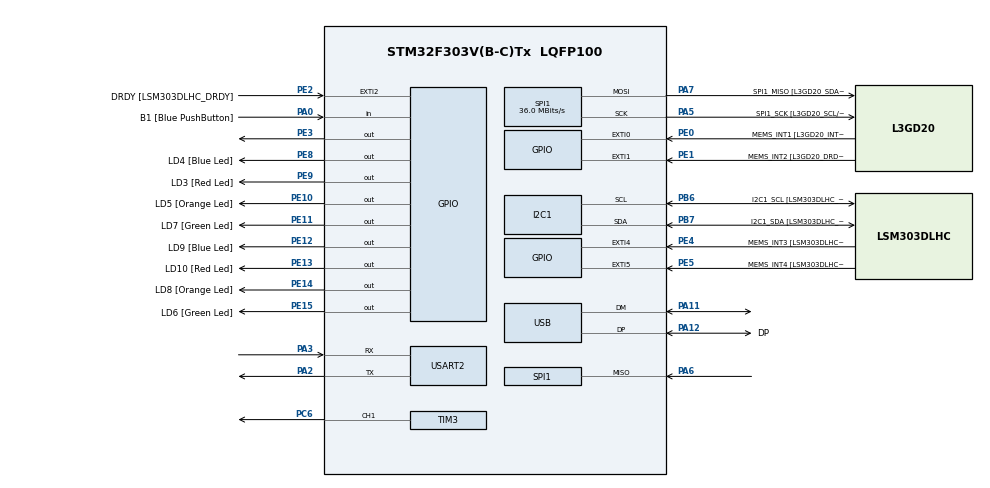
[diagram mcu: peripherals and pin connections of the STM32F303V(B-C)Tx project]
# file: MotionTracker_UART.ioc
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I2C1.Timing=0x00201D2B
I2C1.Timing-I2C=0x2000090E
Mcu.Family=STM32F3
Mcu.Name=STM32F303V(B-C)Tx
Mcu.Package=LQFP100
NVIC.PriorityGroup=NVIC_PRIORITYGROUP_0
NVIC.USART2_IRQn=true\:0\:0\:false\:false\:true\:true\:true\:true
NVIC.USB_LP_CAN_RX0_IRQn=true\:0\:0\:false\:false\:true\:true\:true\:true
PA0.GPIO_Label=B1 [Blue PushButton]
PA0.Signal=GPIO_Input
PA11.Mode=Device
PA11.Signal=USB_DM
PA12.GPIO_Label=DP
PA12.Mode=Device
PA12.Signal=USB_DP
PA13.GPIO_Label=SWDIO
PA13.Mode=Serial_Wire
PA13.Signal=SYS_JTMS-SWDIO
PA14.GPIO_Label=SWCLK
PA14.Mode=Serial_Wire
PA14.Signal=SYS_JTCK-SWCLK
PA2.Mode=Asynchronous
PA2.Signal=USART2_TX
PA3.Mode=Asynchronous
PA3.Signal=USART2_RX
PA5.GPIO_Label=SPI1_SCK [L3GD20_SCL/SPC]
PA5.Mode=Full_Duplex_Master
PA5.Signal=SPI1_SCK
PA6.Mode=Full_Duplex_Master
PA6.Signal=SPI1_MISO
PA7.GPIO_Label=SPI1_MISO [L3GD20_SDA/SDI/SDO]
PA7.Mode=Full_Duplex_Master
PA7.Signal=SPI1_MOSI
PB3.GPIO_Label=SWO
PB3.Signal=SYS_JTDO-TRACESWO
PB6.GPIO_Label=I2C1_SCL [LSM303DLHC_SCL]
PB6.GPIO_Pu=GPIO_PULLUP
PB6.Mode=I2C
PB6.Signal=I2C1_SCL
PB7.GPIO_Label=I2C1_SDA [LSM303DLHC_SDA]
PB7.GPIO_Pu=GPIO_PULLUP
PB7.Mode=I2C
PB7.Signal=I2C1_SDA
PC14-OSC32_IN.GPIO_Label=OSC32_IN
PC14-OSC32_IN.Signal=RCC_OSC32_IN
PC15-OSC32_OUT.GPIO_Label=OSC32_OUT
PC15-OSC32_OUT.Signal=RCC_OSC32_OUT
PC6.Signal=S_TIM3_CH1
PE0.GPIO_Label=MEMS_INT1 [L3GD20_INT1]
PE0.GPIO_ModeDefaultEXTI=GPIO_MODE_EVT_RISING
PE0.Signal=GPXTI0
PE1.GPIO_Label=MEMS_INT2 [L3GD20_DRDY/INT2]
PE1.GPIO_ModeDefaultEXTI=GPIO_MODE_EVT_RISING
PE1.Signal=GPXTI1
PE10.GPIO_Label=LD5 [Orange Led]
PE10.Signal=GPIO_Output
PE11.GPIO_Label=LD7 [Green Led]
PE11.Signal=GPIO_Output
PE12.GPIO_Label=LD9 [Blue Led]
PE12.Signal=GPIO_Output
PE13.GPIO_Label=LD10 [Red Led]
PE13.Signal=GPIO_Output
PE14.GPIO_Label=LD8 [Orange Led]
PE14.Signal=GPIO_Output
PE15.GPIO_Label=LD6 [Green Led]
PE15.Signal=GPIO_Output
PE2.GPIO_Label=DRDY [LSM303DLHC_DRDY]
PE2.GPIO_ModeDefaultEXTI=GPIO_MODE_EVT_RISING
PE2.Signal=GPXTI2
PE3.Signal=GPIO_Output
PE4.GPIO_Label=MEMS_INT3 [LSM303DLHC_INT1]
PE4.GPIO_ModeDefaultEXTI=GPIO_MODE_EVT_RISING
PE4.Signal=GPXTI4
PE5.GPIO_Label=MEMS_INT4 [LSM303DLHC_INT2]
PE5.GPIO_ModeDefaultEXTI=GPIO_MODE_EVT_RISING
PE5.Signal=GPXTI5
PE8.GPIO_Label=LD4 [Blue Led]
PE8.Signal=GPIO_Output
PE9.GPIO_Label=LD3 [Red Led]
PE9.Signal=GPIO_Output
PF0-OSC_IN.GPIO_Label=OSC_IN
PF0-OSC_IN.Mode=HSE-External-Clock-Source
PF0-OSC_IN.Signal=RCC_OSC_IN
PF1-OSC_OUT.GPIO_Label=OSC_OUT
PF1-OSC_OUT.Signal=RCC_OSC_OUT
ProjectManager.HeapSize=0x200
ProjectManager.StackSize=0x400
ProjectManager.TargetToolchain=STM32CubeIDE
RCC.AHBFreq_Value=72000000
RCC.APB1Freq_Value=72000000
RCC.APB1TimFreq_Value=72000000
RCC.APB2Freq_Value=72000000
RCC.APB2TimFreq_Value=72000000
RCC.CortexFreq_Value=72000000
RCC.HCLKFreq_Value=72000000
RCC.HSE_VALUE=8000000
RCC.HSI_VALUE=8000000
RCC.LSE_VALUE=32768
RCC.PLLMUL=RCC_PLL_MUL9
RCC.SYSCLKFreq_VALUE=72000000
RCC.SYSCLKSourceVirtual=RCC_SYSCLKSOURCE_PLLCLK
RCC.USBFreq_Value=72000000
SH.S_TIM3_CH1.0=TIM3_CH1,PWM Generation1 CH1
SPI1.BaudRatePrescaler=SPI_BAUDRATEPRESCALER_2
SPI1.CalculateBaudRate=36.0 MBits/s
SPI1.Direction=SPI_DIRECTION_2LINES
SPI1.Mode=SPI_MODE_MASTER
SPI1.VirtualType=VM_MASTER
TIM3.Channel-PWM\ Generation1\ CH1=TIM_CHANNEL_1
TIM3.Period=999
TIM3.Prescaler=71
USART2.VirtualMode-Asynchronous=VM_ASYNC
VP_TIM3_VS_ClockSourceINT.Mode=Internal
board=STM32F3DISCOVERY

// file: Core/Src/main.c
/* USER CODE BEGIN Header */
/**
  ******************************************************************************
  * @file           : main.c
  * @brief          : Gyroscope-Based Motor Control
  ******************************************************************************
  */
/* USER CODE END Header */

#include "main.h"
#include "tim.h"
#include "usart.h"
#include "gpio.h"
#include "spi.h"
#include "i2c.h"
#include <string.h>
#include <stdio.h>
#include <math.h>
#include "motor.h"

// --- Definitions ---
typedef struct {
    float x;
    float y;
    float z;
    float magnitude;
} L3GD20_Data_t;

#define UART_BUFFER_SIZE 256
#define RX_BUFFER_SIZE 64

// --- Global Variables ---
L3GD20_Data_t gyro_data;
uint8_t current_motor_speed = 0;
uint32_t loop_counter = 0;
char uart_msg[UART_BUFFER_SIZE];

volatile uint8_t motorSpeed = 0;
char debugMsg[UART_BUFFER_SIZE];
uint8_t rxBuffer[RX_BUFFER_SIZE];  // RX_BUFFER_SIZE main.h içinde 64 olarak tanımlanmalı

// --- Function Prototypes ---
void SystemClock_Config(void);
void SendDebugMessage(const char* message);
void L3GD20_Init(void);
void L3GD20_ReadData(L3GD20_Data_t* data);
uint8_t L3GD20_ReadRegister(uint8_t reg);
void L3GD20_WriteRegister(uint8_t reg, uint8_t value);
uint8_t L3GD20_CalculateMotorSpeed(L3GD20_Data_t* gyro_data);
void L3GD20_DisplayOnTerminal(L3GD20_Data_t* gyro_data, uint8_t motor_speed);

// LED Functions - STM32F3 Discovery LEDs
void LED_Init_All(void);
void LED_Set_All(uint8_t state);
void LED_Rainbow_Effect(void);
void LED_Speed_Display(uint8_t speed);
void LED_Gyro_Effect(L3GD20_Data_t* gyro_data);

// Motor functions from motor.c
void HW153_SetMotor(uint8_t speed, uint8_t direction);
#define MOTOR_DIRECTION_FORWARD  1
#define MOTOR_DIRECTION_BACKWARD 0

int main(void)
{
   HAL_Init();
  SystemClock_Config();
  MX_GPIO_Init();
  MX_TIM3_Init();
  MX_USART2_UART_Init();
  MX_SPI1_Init();
  MX_I2C1_Init();

  HAL_Delay(1000);
  HAL_UART_Transmit(&huart2, (uint8_t*)"STM32 Başlatıldı\r\n", 21, HAL_MAX_DELAY);

  Motor_Init();
  L3GD20_Init();
  LED_Init_All();  // Tüm LED'leri başlat

  // Startup LED Show! 🌈
  for(int i = 0; i < 3; i++) {
    LED_Rainbow_Effect();
    HAL_Delay(200);
  }

  HAL_UART_Transmit(&huart2, (uint8_t*)"🌈 LED Show Tamamlandı! 🎉\r\n", 35, HAL_MAX_DELAY);

  while (1)
  {
    L3GD20_ReadData(&gyro_data);
    current_motor_speed = L3GD20_CalculateMotorSpeed(&gyro_data);
    HW153_SetMotor(current_motor_speed, MOTOR_DIRECTION_FORWARD);

    // LED Effects! ✨
    LED_Speed_Display(current_motor_speed);  // Motor hızına göre LED'ler
    LED_Gyro_Effect(&gyro_data);             // Gyroscope efekti

    if (loop_counter % 3 == 0)
    {
        L3GD20_DisplayOnTerminal(&gyro_data, current_motor_speed);
    }

    sprintf(uart_msg, "Gyro[X:%.1f Y:%.1f Z:%.1f] |%.1f| -> Motor:%d%%\r\n",
            gyro_data.x, gyro_data.y, gyro_data.z, gyro_data.magnitude, current_motor_speed);
    SendDebugMessage(uart_msg);

    loop_counter++;
    HAL_Delay(500);
  }
}

void SendDebugMessage(const char* message)
{
    HAL_UART_Transmit(&huart2, (uint8_t*)message, strlen(message), HAL_MAX_DELAY);
}

void L3GD20_Init(void)
{
    HAL_GPIO_WritePin(GPIOE, GPIO_PIN_3, GPIO_PIN_SET);
    HAL_Delay(10);
    L3GD20_WriteRegister(0x20, 0xFF);
    HAL_Delay(10);
    L3GD20_WriteRegister(0x23, 0x00);
    HAL_Delay(10);
}

void L3GD20_ReadData(L3GD20_Data_t* data)
{
    uint8_t buffer[6];
    int16_t raw_x, raw_y, raw_z;

    buffer[0] = L3GD20_ReadRegister(0x28);
    buffer[1] = L3GD20_ReadRegister(0x29);
    buffer[2] = L3GD20_ReadRegister(0x2A);
    buffer[3] = L3GD20_ReadRegister(0x2B);
    buffer[4] = L3GD20_ReadRegister(0x2C);
    buffer[5] = L3GD20_ReadRegister(0x2D);

    raw_x = (int16_t)((buffer[1] << 8) | buffer[0]);
    raw_y = (int16_t)((buffer[3] << 8) | buffer[2]);
    raw_z = (int16_t)((buffer[5] << 8) | buffer[4]);

    data->x = (float)raw_x * 0.00875f;
    data->y = (float)raw_y * 0.00875f;
    data->z = (float)raw_z * 0.00875f;

    data->magnitude = sqrtf(data->x * data->x + data->y * data->y + data->z * data->z);
}

uint8_t L3GD20_ReadRegister(uint8_t reg)
{
    uint8_t tx = reg | 0x80;
    uint8_t rx = 0;

    HAL_GPIO_WritePin(GPIOE, GPIO_PIN_3, GPIO_PIN_RESET);
    HAL_SPI_Transmit(&hspi1, &tx, 1, HAL_MAX_DELAY);
    HAL_SPI_Receive(&hspi1, &rx, 1, HAL_MAX_DELAY);
    HAL_GPIO_WritePin(GPIOE, GPIO_PIN_3, GPIO_PIN_SET);

    return rx;
}

void L3GD20_WriteRegister(uint8_t reg, uint8_t value)
{
    uint8_t tx[2] = {reg, value};
    HAL_GPIO_WritePin(GPIOE, GPIO_PIN_3, GPIO_PIN_RESET);
    HAL_SPI_Transmit(&hspi1, tx, 2, HAL_MAX_DELAY);
    HAL_GPIO_WritePin(GPIOE, GPIO_PIN_3, GPIO_PIN_SET);
}

uint8_t L3GD20_CalculateMotorSpeed(L3GD20_Data_t* gyro_data)
{
    float magnitude = gyro_data->magnitude;
    if (magnitude < 0.5f) return 0;
    if (magnitude > 10.0f) return 100;
    return (uint8_t)(((magnitude - 0.5f) / 9.5f) * 100);
}

void L3GD20_DisplayOnTerminal(L3GD20_Data_t* gyro_data, uint8_t motor_speed)
{
    char msg[128];
    sprintf(msg, "Gyro X: %.2f Y: %.2f Z: %.2f\r\n", gyro_data->x, gyro_data->y, gyro_data->z);
    SendDebugMessage(msg);
    sprintf(msg, "Magnitude: %.2f dps | Motor: %d%%\r\n\r\n", gyro_data->magnitude, motor_speed);
    SendDebugMessage(msg);
}

void Error_Handler(void)
{
  __disable_irq();
  while (1)
  {
    HAL_GPIO_TogglePin(GPIOE, GPIO_PIN_15);
    HAL_Delay(200);
  }
}

void SystemClock_Config(void)
{
    RCC_OscInitTypeDef RCC_OscInitStruct = {0};
    RCC_ClkInitTypeDef RCC_ClkInitStruct = {0};

    RCC_OscInitStruct.OscillatorType = RCC_OSCILLATORTYPE_HSE;
    RCC_OscInitStruct.HSEState = RCC_HSE_BYPASS;
    RCC_OscInitStruct.PLL.PLLState = RCC_PLL_ON;
    RCC_OscInitStruct.PLL.PLLSource = RCC_PLLSOURCE_HSE;
    RCC_OscInitStruct.PLL.PLLMUL = RCC_PLL_MUL9;
    HAL_RCC_OscConfig(&RCC_OscInitStruct);

    RCC_ClkInitStruct.ClockType = RCC_CLOCKTYPE_SYSCLK|RCC_CLOCKTYPE_HCLK
                                  |RCC_CLOCKTYPE_PCLK1|RCC_CLOCKTYPE_PCLK2;
    RCC_ClkInitStruct.SYSCLKSource = RCC_SYSCLKSOURCE_PLLCLK;
    RCC_ClkInitStruct.AHBCLKDivider = RCC_SYSCLK_DIV1;
    RCC_ClkInitStruct.APB1CLKDivider = RCC_HCLK_DIV2;
    RCC_ClkInitStruct.APB2CLKDivider = RCC_HCLK_DIV1;
    HAL_RCC_ClockConfig(&RCC_ClkInitStruct, FLASH_LATENCY_2);
}

// ================================
// 🌈 LED Functions - STM32F3 Discovery LEDs 🌈
// ================================

/**
 * @brief STM32F3 Discovery üzerindeki 8 LED'i başlatır
 * LD3(PE9)-Red, LD4(PE8)-Blue, LD5(PE10)-Orange, LD6(PE15)-Green
 * LD7(PE11)-Green, LD8(PE14)-Orange, LD9(PE12)-Blue, LD10(PE13)-Red
 */
void LED_Init_All(void)
{
    // PE8-PE15 pinleri zaten GPIO_Init'de yapılandırılmış
    // Tüm LED'leri kapat
    LED_Set_All(0);

    HAL_UART_Transmit(&huart2, (uint8_t*)"🔥 8 LED Başlatıldı! 🔥\r\n", 28, HAL_MAX_DELAY);
}

/**
 * @brief Tüm LED'leri açar veya kapatır
 * @param state: 1=Aç, 0=Kapat
 */
void LED_Set_All(uint8_t state)
{
    GPIO_PinState pin_state = state ? GPIO_PIN_SET : GPIO_PIN_RESET;

    HAL_GPIO_WritePin(GPIOE, GPIO_PIN_8, pin_state);   // LD4 - Blue
    HAL_GPIO_WritePin(GPIOE, GPIO_PIN_9, pin_state);   // LD3 - Red
    HAL_GPIO_WritePin(GPIOE, GPIO_PIN_10, pin_state);  // LD5 - Orange
    HAL_GPIO_WritePin(GPIOE, GPIO_PIN_11, pin_state);  // LD7 - Green
    HAL_GPIO_WritePin(GPIOE, GPIO_PIN_12, pin_state);  // LD9 - Blue
    HAL_GPIO_WritePin(GPIOE, GPIO_PIN_13, pin_state);  // LD10 - Red
    HAL_GPIO_WritePin(GPIOE, GPIO_PIN_14, pin_state);  // LD8 - Orange
    HAL_GPIO_WritePin(GPIOE, GPIO_PIN_15, pin_state);  // LD6 - Green
}

/**
 * @brief Gökkuşağı efekti - LED'leri sırayla yakar
 */
void LED_Rainbow_Effect(void)
{
    uint16_t leds[] = {GPIO_PIN_8, GPIO_PIN_9, GPIO_PIN_10, GPIO_PIN_11,
                       GPIO_PIN_12, GPIO_PIN_13, GPIO_PIN_14, GPIO_PIN_15};

    // Sırayla yak
    for(int i = 0; i < 8; i++) {
        HAL_GPIO_WritePin(GPIOE, leds[i], GPIO_PIN_SET);
        HAL_Delay(50);
    }

    // Sırayla söndür
    for(int i = 0; i < 8; i++) {
        HAL_GPIO_WritePin(GPIOE, leds[i], GPIO_PIN_RESET);
        HAL_Delay(50);
    }
}

/**
 * @brief Motor hızına göre LED gösterimi
 * @param speed: Motor hızı (0-100%)
 */
void LED_Speed_Display(uint8_t speed)
{
    // Hızı 8 LED'e böl (her LED %12.5'lik dilimi temsil eder)
    uint8_t led_count = (speed * 8) / 100;

    // Tüm LED'leri söndür
    LED_Set_All(0);

    // Hıza göre LED'leri yak
    uint16_t leds[] = {GPIO_PIN_8, GPIO_PIN_9, GPIO_PIN_10, GPIO_PIN_11,
                       GPIO_PIN_12, GPIO_PIN_13, GPIO_PIN_14, GPIO_PIN_15};

    for(int i = 0; i < led_count && i < 8; i++) {
        HAL_GPIO_WritePin(GPIOE, leds[i], GPIO_PIN_SET);
    }

    // En yüksek LED'i yanıp söndür (motor çalışıyor göstergesi)
    if(speed > 0 && led_count > 0) {
        HAL_GPIO_TogglePin(GPIOE, leds[led_count-1]);
    }
}

/**
 * @brief Gyroscope verilerine göre LED efekti
 * @param gyro_data: Gyroscope verileri
 */
void LED_Gyro_Effect(L3GD20_Data_t* gyro_data)
{
    // X eksenine göre mavi LED'ler (PE8, PE12)
    if(fabsf(gyro_data->x) > 2.0f) {
        HAL_GPIO_WritePin(GPIOE, GPIO_PIN_8, GPIO_PIN_SET);   // LD4 - Blue
        HAL_GPIO_WritePin(GPIOE, GPIO_PIN_12, GPIO_PIN_SET);  // LD9 - Blue
    }

    // Y eksenine göre kırmızı LED'ler (PE9, PE13)
    if(fabsf(gyro_data->y) > 2.0f) {
        HAL_GPIO_WritePin(GPIOE, GPIO_PIN_9, GPIO_PIN_SET);   // LD3 - Red
        HAL_GPIO_WritePin(GPIOE, GPIO_PIN_13, GPIO_PIN_SET);  // LD10 - Red
    }

    // Z eksenine göre yeşil LED'ler (PE11, PE15)
    if(fabsf(gyro_data->z) > 2.0f) {
        HAL_GPIO_WritePin(GPIOE, GPIO_PIN_11, GPIO_PIN_SET);  // LD7 - Green
        HAL_GPIO_WritePin(GPIOE, GPIO_PIN_15, GPIO_PIN_SET);  // LD6 - Green
    }

    // Magnitude'e göre turuncu LED'ler (PE10, PE14)
    if(gyro_data->magnitude > 5.0f) {
        HAL_GPIO_WritePin(GPIOE, GPIO_PIN_10, GPIO_PIN_SET);  // LD5 - Orange
        HAL_GPIO_WritePin(GPIOE, GPIO_PIN_14, GPIO_PIN_SET);  // LD8 - Orange
    }
}
